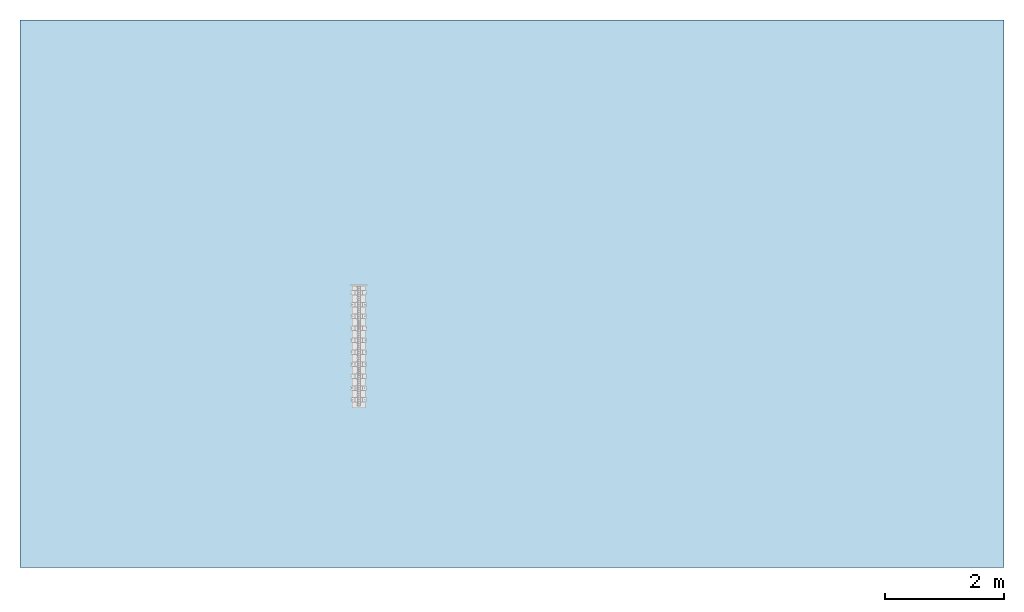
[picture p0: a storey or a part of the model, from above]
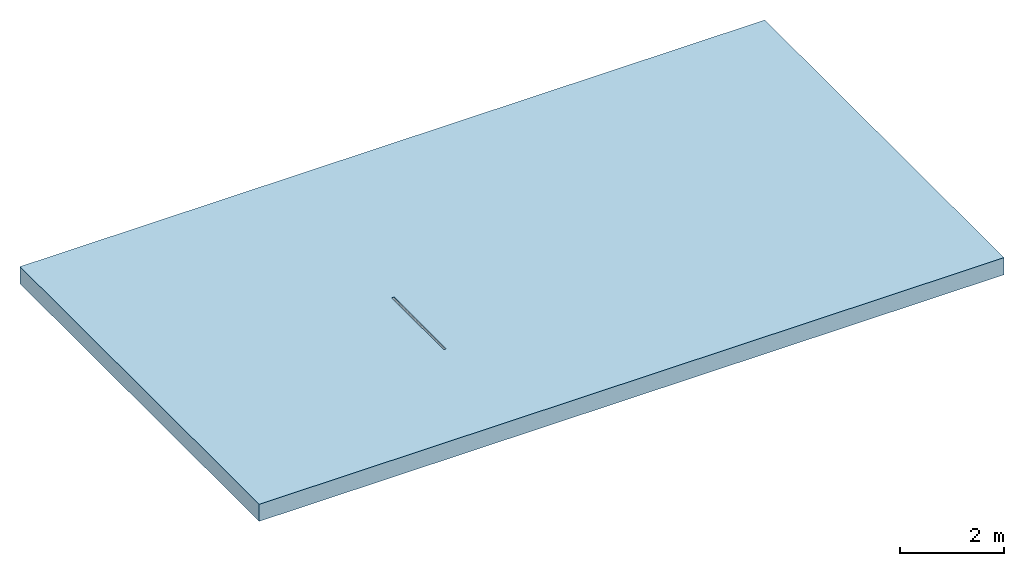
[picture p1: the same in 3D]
Properties of the parts of a building model (IFC2X3)

# File
Description: ViewDefinition [CoordinationView]
File name: 32803 - Q-Guard Edge - G.S.ifc
Time: 2013-09-04T16:56:59
Written by: Autodesk Revit 2013
Made in: 20120221_2030(x64)

# IfcProject, Project Number
LongName: Project Name; Phase: Project Status

# IfcSite, Default
RefLatitude: 42, 21, 30, 344238; RefLongitude: -71, -3, -35, -194702; RefElevation: 0 mm

# IfcBuilding
Pset_BuildingCommon - NumberOfStoreys: 1
Other - Project Address: ## Street City, State Zip; Project Name: Project Name; Project Number: Project Number; Project Status: Project Status; Project Issue Date: Issue Date; Client Name: Owner

# IfcBuildingStorey, Level 1
LongName: Level 1; Elevation: 0 mm
Constraints - Elevation Base: 0; Elevation: 0 mm
Graphics - Symbol: M_Level Head - Circle: M_Level Head - Circle; Symbol at End 2 Default: yes; Line Pattern: Center; Symbol at End 1 Default: no; Line Weight: 1; Color: 0
Dimensions - Computation Height: 0 mm
Identity Data - Name: Level 1; Structural: no; Building Story: yes

# IfcFlowTerminal: 32803 - Q-Guard Edge - G.S, Qmax 225:32803 - Q-Guard Edge - G.S:32803 - Q-Guard Edge - G.S:351197
In: Level 1
Identity Data - Mark: 62; Product Brochure: http://www.aco.co.uk/download.php?id=220; Address: ACO Business Park, Hitchin Road, Shefford, Bedfordshire, United Kingdom SG17 5TE; Type Comments: ACO Qmax 225 channel assembly complete with ACO Q-Guard galvanised steel edge rail; Model: ACO Qmax 225; Fax: +44 (0)1462 815895; Assembly Code: D2040; Manufacturer: ACO Technologies plc - ACO Water Management Division; Telephone: +44 (0)1462 816666; OmniClass Title: Rainwater Removal; e-mail Sales: customersupport@aco.co.uk; Installation Guidelines: http://www.aco.co.uk/download.php?id=220; Product Page URL: http://www.aco.co.uk/product_detail.php?id=79; Assembly Description: Rain Water Drainage; e-mail Technical: technical@aco.co.uk; URL: www.aco.co.uk; OmniClass Number: 23.70.50.24; Product Code: 32803; Price: POA - contact ACO; Cost: 0; Model Description: High capacity slot drainage channel system; Maintenance Guidelines: http://www.aco.co.uk/download.php?id=220
Construction - 42221_225 End Cap (at Male end): no; 42221_225 End Cap (at Female end): no; 32995_150-225 Step Connector: no; V_CoarseE1: yes; E5-QSlot-GalvSteel: no; E3-QFlow-GalvSteel: no; V_Coarse_E5: no; E1-QFlow-DuctileIron: no; E2-QGuard-DuctileIron: no; E4-QGuard-GalvSteel: yes
Phasing - Phase Created: New Construction
Constraints - Level: Level: Level 1; Moves With Nearby Elements: no
Model Properties - Multi-functional End Cap - Channel Recycled Material Content: Variable %; Multi-functional End Cap - Seal Material: Chloroprene; 150-225 Step Connector - Product Code: 32995; Multi-functional End Cap - Dimensions: Ø290mm x 240mm (ØxL); Multi-functional End Cap - Seal Recycled Material Content: 0%; Multi-functional End Cap - Channel Recyclable: Fully recyclable; Multi-functional End Cap - Seal Recyclable: Fully recyclable; Multi-functional End Cap - Product Code: 42221; 150-225 Step Connector - Dimensions: Ø310mm x 25mm (ØxL); Multi-functional End Cap - Seal Colour: Black; 150-225 Step Connector - Colour: Black Medium Density Polyethylene; Multi-functional End Cap - Channel Material: Medium Density Polyethylene; 150-225 Step Connector - Recycled Material Content: 0%; 150-225 Step Connector - Recyclable: Fully recyclable; 150-225 Step Connector - Model Description: High capacity slot drainage channel system; Multi-functional End Cap - Channel Colour: Black Medium Density Polyethylene; 150-225 Step Connector - Weight: 0.4 kg; Multi-functional End Cap - Model Description: High capacity slot drainage channel system; 150-225 Step Connector - Material: High Density Polyethylene; Multi-functional End Cap - Weight: 1.4 kg
General - SerialNumber: 0; TagNumber: 0
Materials and Finishes - Edge Rail Material: Steel; Channel Colour: Black; Channel Material: Medium Density Polyethylene; Edge Rail Finish: Galvanised; Seal Colour: Black; Seal Material: Chloroprene; Edge Rail Colour: Silver
Data - Installation - Concrete Grade: Refer to brochure; Concrete Surround Volume - Load Class F 900: 0.345 m³/m; Concrete Surround Volume - Load Class A 15 - E 600: 0.255 m³/m; Load Class: A 15 - F 900; Product Standard: BS EN 1433:2002 CE marked; Drainage Slot Width: 10mm; Product Weight: 15.3 kg; Installation - Reinforcement Details: Refer to brochure; ACO Hydraulic Design Software: http://www.acodesign.co.uk; Drainage Slot Intake Area: 8356mm²/m; Channel C.S.A: 39761mm²; Invert Depth: 425mm; Product Dimensions: 2000mm x 290mm x 480mm (LxWxH); Hydraulic Performance: http://www.aco.co.uk/download.php?id=220
Green Building Properties - Seal Recyclable: Fully recyclable; Channel Recyclable: Fully recyclable; Edge Rail Recycled Material Content: Between 40% - 90%; Edge Rail Recyclable: Fully recyclable; Channel Recycled Material Content: Variable %; Seal Recycled Material Content: 0%
Dimensions - Depth Overall: 480 mm; Floor Opening Width: 55 mm; BoreCentre: 311.5 mm; Length: 2000 mm; Width Overall: 290 mm
Other - Created by: www.aco.co.uk; Revision: 1

# IfcOpeningElement: Opening
In: Level 1
Structural - Enable Analytical Model: no; Structural: no
Dimensions - Area: 151360000 mm2; Volume: 60359000000 mm3; Perimeter: 51360 mm; Thickness: 400 mm
Constraints - Room Bounding: yes; Height Offset From Level: 0 mm; Level: Level: Level 1; Related to Mass: no
Phasing - Phase Created: New Construction
Construction - Function: 0; Default Thickness: 400 mm
Analytical Properties - Absorptance: 0.1; Roughness: 1
Graphics - Coarse Scale Fill Color: 0
Materials and Finishes - Structural Material: Plant

# IfcSlab: Floor:Generic Floor - 400mm, Floor:Generic Floor - 400mm:193825
In: Level 1
PredefinedType: FLOOR; Material: Plant 400 mm
Structural - Enable Analytical Model: no; Structural: no
Dimensions - Area: 151360000 mm2; Volume: 60359000000 mm3; Perimeter: 51360 mm; Thickness: 400 mm
Constraints - Room Bounding: yes; Height Offset From Level: 0 mm; Level: Level: Level 1; Related to Mass: no
Phasing - Phase Created: New Construction
Pset_SlabCommon - Reference: Generic Floor - 400mm; IsExternal: no; LoadBearing: yes
Construction - Function: 0; Default Thickness: 400 mm
Analytical Properties - Absorptance: 0.1; Roughness: 1
Graphics - Coarse Scale Fill Color: 0
Materials and Finishes - Structural Material: Plant
